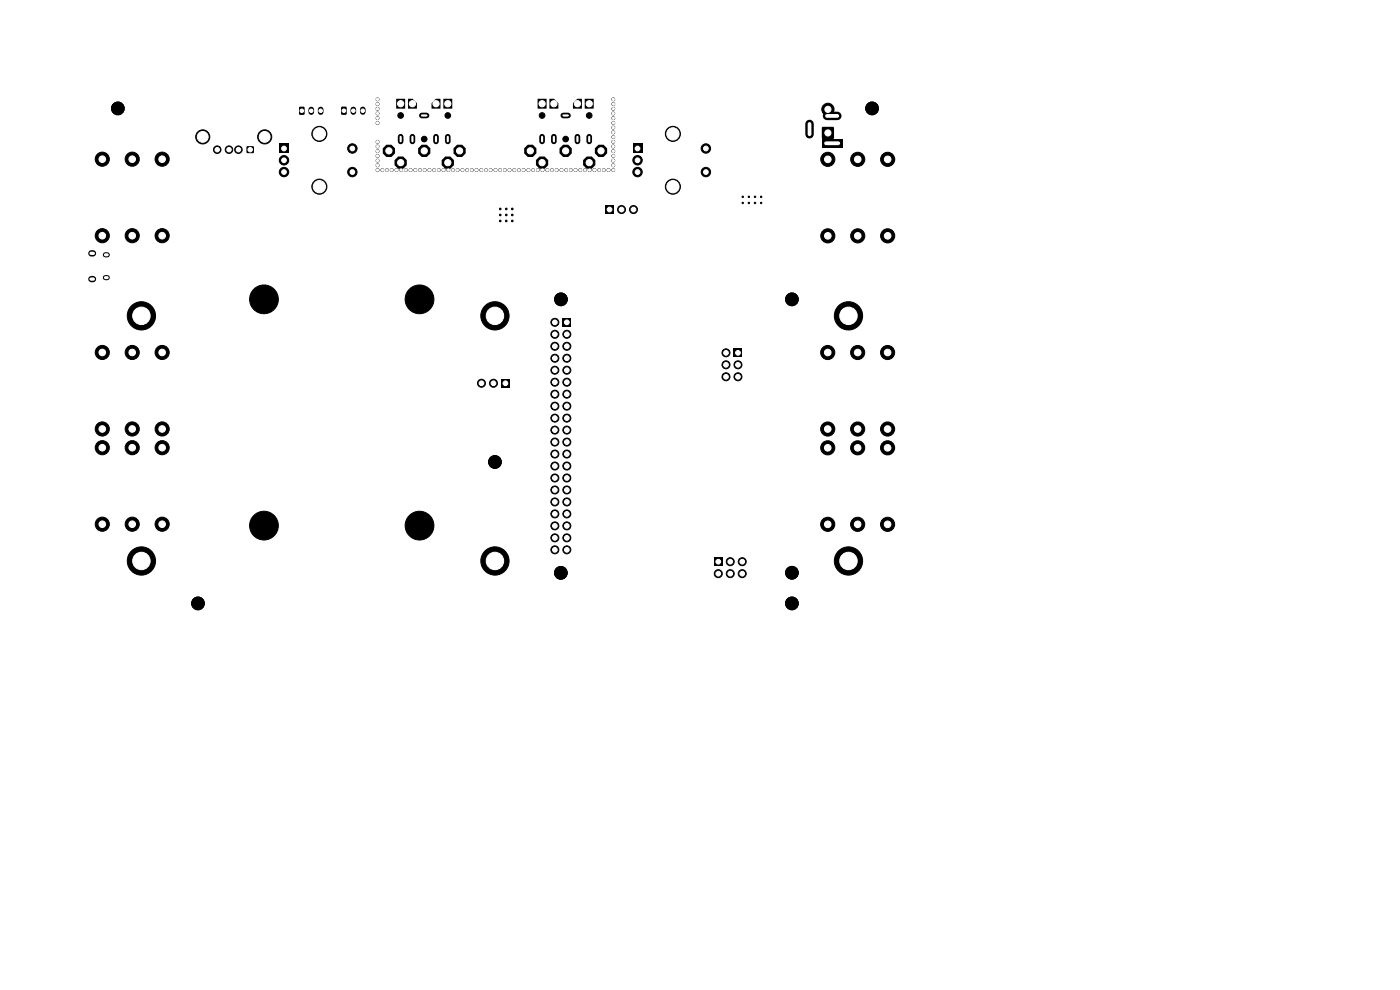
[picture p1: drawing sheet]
<svg xmlns="http://www.w3.org/2000/svg" width="297mm" height="210mm" viewBox="0 0 297 210" stroke-linecap="round" stroke-linejoin="round" font-family="sans-serif">
<g fill="#000" stroke="#000" stroke-width=".21">
<circle cx="21.7" cy="33.8" r="1.5"/>
<circle cx="25" cy="23" r="1.35"/>
<circle cx="28.1" cy="33.8" r="1.5"/>
<circle cx="34.4" cy="33.8" r="1.5"/>
<circle cx="43" cy="29" r="1.5"/>
<circle cx="46.1" cy="31.7" r=".8"/>
<circle cx="48.6" cy="31.7" r=".8"/>
<circle cx="50.6" cy="31.7" r=".8"/>
<circle cx="56.1" cy="29" r="1.5"/>
<circle cx="60.2" cy="36.5" r="1"/>
<circle cx="60.3" cy="34" r="1"/>
<circle cx="67.7" cy="28.4" r="1.6"/>
<circle cx="67.7" cy="39.6" r="1.6"/>
<circle cx="74.7" cy="36.5" r="1"/>
<circle cx="74.7" cy="31.5" r="1"/>
<circle cx="80.1" cy="33.1" r=".3"/>
<circle cx="80.1" cy="24.1" r=".3"/>
<circle cx="80.1" cy="36.1" r=".3"/>
<circle cx="80.1" cy="23.1" r=".3"/>
<circle cx="80.1" cy="21.1" r=".3"/>
<circle cx="80.1" cy="26.1" r=".3"/>
<circle cx="80.1" cy="34.1" r=".3"/>
<circle cx="80.1" cy="31.1" r=".3"/>
<circle cx="80.1" cy="22.1" r=".3"/>
<circle cx="80.1" cy="30.1" r=".3"/>
<circle cx="80.1" cy="25.1" r=".3"/>
<circle cx="80.1" cy="32.1" r=".3"/>
<circle cx="80.1" cy="35.1" r=".3"/>
<circle cx="81.1" cy="36.1" r=".3"/>
<circle cx="82.1" cy="36.1" r=".3"/>
<circle cx="83.1" cy="36.1" r=".3"/>
<circle cx="84.1" cy="36.1" r=".3"/>
<circle cx="85" cy="24.5" r=".6"/>
<circle cx="85.1" cy="36.1" r=".3"/>
<circle cx="86.1" cy="36.1" r=".3"/>
<circle cx="87.1" cy="36.1" r=".3"/>
<circle cx="88.1" cy="36.1" r=".3"/>
<circle cx="89.1" cy="36.1" r=".3"/>
<circle cx="90" cy="29.5" r=".6"/>
<circle cx="90.1" cy="36.1" r=".3"/>
<circle cx="91.1" cy="36.1" r=".3"/>
<circle cx="92.1" cy="36.1" r=".3"/>
<circle cx="93.1" cy="36.1" r=".3"/>
<circle cx="94.1" cy="36.1" r=".3"/>
<circle cx="95" cy="24.5" r=".6"/>
<circle cx="95.1" cy="36.1" r=".3"/>
<circle cx="96.1" cy="36.1" r=".3"/>
<circle cx="97.1" cy="36.1" r=".3"/>
<circle cx="98.1" cy="36.1" r=".3"/>
<circle cx="99.1" cy="36.1" r=".3"/>
<circle cx="100.1" cy="36.1" r=".3"/>
<circle cx="101.1" cy="36.1" r=".3"/>
<circle cx="102.1" cy="36.1" r=".3"/>
<circle cx="103.1" cy="36.1" r=".3"/>
<circle cx="104.1" cy="36.1" r=".3"/>
<circle cx="105.1" cy="36.1" r=".3"/>
<circle cx="106.1" cy="36.1" r=".3"/>
<circle cx="107.1" cy="36.1" r=".3"/>
<circle cx="108.1" cy="36.1" r=".3"/>
<circle cx="109.1" cy="36.1" r=".3"/>
<circle cx="110.1" cy="36.1" r=".3"/>
<circle cx="111.1" cy="36.1" r=".3"/>
<circle cx="112.1" cy="36.1" r=".3"/>
<circle cx="113.1" cy="36.1" r=".3"/>
<circle cx="114.1" cy="36.1" r=".3"/>
<circle cx="115" cy="24.5" r=".6"/>
<circle cx="115.1" cy="36.1" r=".3"/>
<circle cx="116.1" cy="36.1" r=".3"/>
<circle cx="117.1" cy="36.1" r=".3"/>
<circle cx="118.1" cy="36.1" r=".3"/>
<circle cx="119.1" cy="36.1" r=".3"/>
<circle cx="120" cy="29.5" r=".6"/>
<circle cx="120.1" cy="36.1" r=".3"/>
<circle cx="121.1" cy="36.1" r=".3"/>
<circle cx="122.1" cy="36.1" r=".3"/>
<circle cx="123.1" cy="36.1" r=".3"/>
<circle cx="124.1" cy="36.1" r=".3"/>
<circle cx="125" cy="24.5" r=".6"/>
<circle cx="125.1" cy="36.1" r=".3"/>
<circle cx="126.1" cy="36.1" r=".3"/>
<circle cx="127.1" cy="36.1" r=".3"/>
<circle cx="128.1" cy="36.1" r=".3"/>
<circle cx="129.1" cy="36.1" r=".3"/>
<circle cx="130.1" cy="33.1" r=".3"/>
<circle cx="130.1" cy="24.1" r=".3"/>
<circle cx="130.1" cy="29.1" r=".3"/>
<circle cx="130.1" cy="34.1" r=".3"/>
<circle cx="130.1" cy="23.1" r=".3"/>
<circle cx="130.1" cy="36.1" r=".3"/>
<circle cx="130.1" cy="21.1" r=".3"/>
<circle cx="130.1" cy="31.1" r=".3"/>
<circle cx="130.1" cy="26.1" r=".3"/>
<circle cx="130.1" cy="28.1" r=".3"/>
<circle cx="130.1" cy="25.1" r=".3"/>
<circle cx="130.1" cy="32.1" r=".3"/>
<circle cx="130.1" cy="30.1" r=".3"/>
<circle cx="130.1" cy="27.1" r=".3"/>
<circle cx="130.1" cy="35.1" r=".3"/>
<circle cx="130.1" cy="22.1" r=".3"/>
<circle cx="135.2" cy="36.5" r="1"/>
<circle cx="135.2" cy="34" r="1"/>
<circle cx="142.7" cy="28.4" r="1.6"/>
<circle cx="142.8" cy="39.6" r="1.6"/>
<circle cx="149.7" cy="36.5" r="1"/>
<circle cx="149.7" cy="31.5" r="1"/>
<circle cx="175.6" cy="33.8" r="1.5"/>
<circle cx="175.6" cy="23.2" r="1.3"/>
<circle cx="182" cy="33.8" r="1.5"/>
<circle cx="185" cy="23" r="1.35"/>
<circle cx="188.3" cy="33.8" r="1.5"/>
<circle cx="21.7" cy="50" r="1.5"/>
<circle cx="28.1" cy="50" r="1.5"/>
<circle cx="34.4" cy="50" r="1.5"/>
<circle cx="106.1" cy="46.9" r=".17"/>
<circle cx="106.1" cy="44.3" r=".17"/>
<circle cx="106.1" cy="45.6" r=".17"/>
<circle cx="107.4" cy="46.9" r=".17"/>
<circle cx="107.4" cy="45.6" r=".17"/>
<circle cx="107.4" cy="44.3" r=".17"/>
<circle cx="108.7" cy="46.9" r=".17"/>
<circle cx="108.7" cy="44.3" r=".17"/>
<circle cx="108.7" cy="45.6" r=".17"/>
<circle cx="131.9" cy="44.4" r=".85"/>
<circle cx="134.4" cy="44.4" r=".85"/>
<circle cx="157.6" cy="41.8" r=".15"/>
<circle cx="157.6" cy="43.1" r=".15"/>
<circle cx="158.9" cy="43.1" r=".15"/>
<circle cx="158.9" cy="41.8" r=".15"/>
<circle cx="160.2" cy="43.1" r=".15"/>
<circle cx="160.2" cy="41.8" r=".15"/>
<circle cx="161.5" cy="43.1" r=".15"/>
<circle cx="161.5" cy="41.8" r=".15"/>
<circle cx="175.6" cy="50" r="1.5"/>
<circle cx="182" cy="50" r="1.5"/>
<circle cx="188.3" cy="50" r="1.5"/>
<circle cx="21.7" cy="74.8" r="1.5"/>
<circle cx="28.1" cy="74.8" r="1.5"/>
<circle cx="30" cy="67" r="3"/>
<circle cx="34.4" cy="74.8" r="1.5"/>
<circle cx="56" cy="63.5" r="3"/>
<circle cx="56" cy="63.5" r="1.35"/>
<circle cx="89" cy="63.5" r="3"/>
<circle cx="89" cy="63.5" r="1.35"/>
<circle cx="105" cy="67" r="3"/>
<circle cx="117.7" cy="78.5" r=".85"/>
<circle cx="117.7" cy="76" r=".85"/>
<circle cx="117.7" cy="68.4" r=".85"/>
<circle cx="117.7" cy="73.5" r=".85"/>
<circle cx="117.7" cy="70.9" r=".85"/>
<circle cx="119" cy="63.5" r="1.35"/>
<circle cx="120.3" cy="78.5" r=".85"/>
<circle cx="120.3" cy="70.9" r=".85"/>
<circle cx="120.3" cy="73.5" r=".85"/>
<circle cx="120.3" cy="76" r=".85"/>
<circle cx="154" cy="79.9" r=".85"/>
<circle cx="154" cy="74.8" r=".85"/>
<circle cx="154" cy="77.4" r=".85"/>
<circle cx="156.6" cy="79.9" r=".85"/>
<circle cx="156.6" cy="77.4" r=".85"/>
<circle cx="168" cy="63.5" r="1.35"/>
<circle cx="175.6" cy="74.8" r="1.5"/>
<circle cx="180" cy="67" r="3"/>
<circle cx="181.9" cy="74.8" r="1.5"/>
<circle cx="188.3" cy="74.8" r="1.5"/>
<circle cx="21.7" cy="95" r="1.5"/>
<circle cx="21.7" cy="91" r="1.5"/>
<circle cx="28.1" cy="95" r="1.5"/>
<circle cx="28.1" cy="91" r="1.5"/>
<circle cx="34.4" cy="95" r="1.5"/>
<circle cx="34.4" cy="91" r="1.5"/>
<circle cx="102.1" cy="81.3" r=".85"/>
<circle cx="104.7" cy="81.3" r=".85"/>
<circle cx="105" cy="98" r="1.35"/>
<circle cx="117.7" cy="93.8" r=".85"/>
<circle cx="117.7" cy="96.3" r=".85"/>
<circle cx="117.7" cy="88.7" r=".85"/>
<circle cx="117.7" cy="81.1" r=".85"/>
<circle cx="117.7" cy="83.6" r=".85"/>
<circle cx="117.7" cy="86.2" r=".85"/>
<circle cx="117.7" cy="91.2" r=".85"/>
<circle cx="117.7" cy="98.9" r=".85"/>
<circle cx="120.3" cy="86.2" r=".85"/>
<circle cx="120.3" cy="83.6" r=".85"/>
<circle cx="120.3" cy="93.8" r=".85"/>
<circle cx="120.3" cy="96.3" r=".85"/>
<circle cx="120.3" cy="88.7" r=".85"/>
<circle cx="120.3" cy="81.1" r=".85"/>
<circle cx="120.3" cy="91.2" r=".85"/>
<circle cx="120.3" cy="98.9" r=".85"/>
<circle cx="175.6" cy="91" r="1.5"/>
<circle cx="175.6" cy="95" r="1.5"/>
<circle cx="181.9" cy="91" r="1.5"/>
<circle cx="181.9" cy="95" r="1.5"/>
<circle cx="188.3" cy="91" r="1.5"/>
<circle cx="188.3" cy="95" r="1.5"/>
<circle cx="21.7" cy="111.2" r="1.5"/>
<circle cx="28.1" cy="111.2" r="1.5"/>
<circle cx="30" cy="119" r="3"/>
<circle cx="34.4" cy="111.2" r="1.5"/>
<circle cx="56" cy="111.5" r="3"/>
<circle cx="56" cy="111.5" r="1.35"/>
<circle cx="89" cy="111.5" r="3"/>
<circle cx="89" cy="111.5" r="1.35"/>
<circle cx="105" cy="119" r="3"/>
<circle cx="117.7" cy="103.9" r=".85"/>
<circle cx="117.7" cy="106.5" r=".85"/>
<circle cx="117.7" cy="116.6" r=".85"/>
<circle cx="117.7" cy="114.1" r=".85"/>
<circle cx="117.7" cy="109" r=".85"/>
<circle cx="117.7" cy="111.6" r=".85"/>
<circle cx="117.7" cy="101.4" r=".85"/>
<circle cx="120.3" cy="101.4" r=".85"/>
<circle cx="120.3" cy="103.9" r=".85"/>
<circle cx="120.3" cy="114.1" r=".85"/>
<circle cx="120.3" cy="116.6" r=".85"/>
<circle cx="120.3" cy="106.5" r=".85"/>
<circle cx="120.3" cy="109" r=".85"/>
<circle cx="120.3" cy="111.6" r=".85"/>
<circle cx="154.9" cy="119.2" r=".85"/>
<circle cx="157.5" cy="119.2" r=".85"/>
<circle cx="175.6" cy="111.2" r="1.5"/>
<circle cx="180" cy="119" r="3"/>
<circle cx="181.9" cy="111.2" r="1.5"/>
<circle cx="188.3" cy="111.2" r="1.5"/>
<circle cx="42" cy="128" r="1.35"/>
<circle cx="119" cy="121.5" r="1.35"/>
<circle cx="152.4" cy="121.7" r=".85"/>
<circle cx="154.9" cy="121.7" r=".85"/>
<circle cx="157.5" cy="121.7" r=".85"/>
<circle cx="168" cy="121.5" r="1.35"/>
<circle cx="168" cy="128" r="1.35"/>
</g>
<g fill="none" stroke="#000" stroke-width="1.2">
<path d="M66 23.2v.6M68 23.2v.6M75 23.2v.6M77 23.2v.6M85 29v1M87.5 29v1M89.5 24.5h1M92.5 29v1M95 29v1M115 29v1M117.5 29v1M119.5 24.5h1"/>
<path d="M122.5 29v1M125 29v1"/>
</g>
<g fill="#000">
<path d="M52.4 31.1h1.4v1.3h-1.4zM59.2 30.5h2.1v2h-2.1zM63.5 22.7l.9-.1 .2 .2v1.3l-.1 .3h-.8l-.3-.2zM72.4 22.7l.9-.1 .2 .2 .1 1.3-.2 .2-.8 .1-.2-.2zM84.1 21h1.8v2h-1.8zM86.6 21h.9l.9 .9v1.1h-1.8zM91.6 21.9l.9-.9h.9v2h-1.8zM94.1 21h1.8v2h-1.8zM114.1 21h1.8v2h-1.8zM116.6 21h.9l.9 .9v1.1h-1.8zM121.6 21.9l.9-.9h.9v2h-1.8zM124.1 21h1.8v2h-1.8z"/>
<path d="M134.3 30.5h1.9v2h-1.9zM174.4 27h2.5v2.4h-2.5zM174.3 29.5h4.4v1.8h-4.4zM128.5 43.6h1.7v1.7h-1.7zM119.4 67.5h1.7v1.7h-1.7zM155.7 74h1.7v1.7h-1.7zM106.4 80.5h1.7v1.7h-1.7zM151.5 118.3h1.7v1.7h-1.7z"/>
<circle cx="82.5" cy="32" r="1.4"/>
<circle cx="85" cy="34.5" r="1.4"/>
<circle cx="90" cy="32" r="1.4"/>
<circle cx="95" cy="34.5" r="1.4"/>
<circle cx="97.5" cy="32" r="1.4"/>
<circle cx="112.5" cy="32" r="1.4"/>
<circle cx="115" cy="34.5" r="1.4"/>
<circle cx="120" cy="32" r="1.4"/>
<circle cx="125" cy="34.5" r="1.4"/>
<circle cx="127.5" cy="32" r="1.4"/>
</g>
<path d="M171.7 26.3v2.2M175.4 24.6h2.2" fill="none" stroke="#000" stroke-width="1.8"/>
<path d="M19.4 53.7h.3M19.4 59.2h.3" fill="none" stroke="#000" stroke-width="1.3"/>
<path d="M22.4 54.1h.4M22.4 58.9h.4" fill="none" stroke="#000" stroke-width="1.1"/>
<path d="M85 29v1M87.5 29v1M89.5 24.5h1M92.5 29v1M95 29v1M115 29v1M117.5 29v1M119.5 24.5h1M122.5 29v1M125 29v1" fill="none" stroke="#fff" stroke-width=".45"/>
<g fill="#fff" stroke="#fff" stroke-width=".21">
<circle cx="28" cy="50" r=".7"/>
<circle cx="28" cy="33.8" r=".7"/>
<circle cx="21.7" cy="50" r=".7"/>
<circle cx="21.7" cy="33.8" r=".7"/>
<circle cx="34.4" cy="50" r=".7"/>
<circle cx="34.4" cy="33.8" r=".7"/>
<circle cx="28" cy="111.2" r=".7"/>
<circle cx="28" cy="95" r=".7"/>
<circle cx="21.7" cy="111.2" r=".7"/>
<circle cx="21.7" cy="95" r=".7"/>
<circle cx="34.4" cy="111.2" r=".7"/>
<circle cx="34.4" cy="95" r=".7"/>
<circle cx="175.6" cy="28.2" r=".65"/>
<circle cx="175.6" cy="23.2" r=".65"/>
<circle cx="28" cy="91" r=".7"/>
<circle cx="28" cy="74.8" r=".7"/>
<circle cx="21.7" cy="91" r=".7"/>
<circle cx="21.7" cy="74.8" r=".7"/>
<circle cx="34.4" cy="91" r=".7"/>
<circle cx="34.4" cy="74.8" r=".7"/>
<circle cx="181.9" cy="95" r=".7"/>
<circle cx="181.9" cy="111.2" r=".7"/>
<circle cx="188.3" cy="95" r=".7"/>
<circle cx="188.3" cy="111.2" r=".7"/>
<circle cx="175.6" cy="95" r=".7"/>
<circle cx="175.6" cy="111.2" r=".7"/>
<circle cx="129.3" cy="44.5" r=".5"/>
<circle cx="131.9" cy="44.5" r=".5"/>
<circle cx="134.4" cy="44.5" r=".5"/>
<circle cx="80.1" cy="21.1" r=".25"/>
<circle cx="80.1" cy="22.1" r=".25"/>
<circle cx="80.1" cy="23.1" r=".25"/>
<circle cx="80.1" cy="24.1" r=".25"/>
<circle cx="80.1" cy="25.1" r=".25"/>
<circle cx="80.1" cy="26.1" r=".25"/>
<circle cx="80.1" cy="30.1" r=".25"/>
<circle cx="80.1" cy="31.1" r=".25"/>
<circle cx="80.1" cy="32.1" r=".25"/>
<circle cx="80.1" cy="33.1" r=".25"/>
<circle cx="80.1" cy="34.1" r=".25"/>
<circle cx="80.1" cy="35.1" r=".25"/>
<circle cx="80.1" cy="36.1" r=".25"/>
<circle cx="81.1" cy="36.1" r=".25"/>
<circle cx="82.1" cy="36.1" r=".25"/>
<circle cx="83.1" cy="36.1" r=".25"/>
<circle cx="84.1" cy="36.1" r=".25"/>
<circle cx="85.1" cy="36.1" r=".25"/>
<circle cx="86.1" cy="36.1" r=".25"/>
<circle cx="87.1" cy="36.1" r=".25"/>
<circle cx="88.1" cy="36.1" r=".25"/>
<circle cx="89.1" cy="36.1" r=".25"/>
<circle cx="90.1" cy="36.1" r=".25"/>
<circle cx="91.1" cy="36.1" r=".25"/>
<circle cx="92.1" cy="36.1" r=".25"/>
<circle cx="93.1" cy="36.1" r=".25"/>
<circle cx="94.1" cy="36.1" r=".25"/>
<circle cx="95.1" cy="36.1" r=".25"/>
<circle cx="96.1" cy="36.1" r=".25"/>
<circle cx="97.1" cy="36.1" r=".25"/>
<circle cx="98.1" cy="36.1" r=".25"/>
<circle cx="99.1" cy="36.1" r=".25"/>
<circle cx="100.1" cy="36.1" r=".25"/>
<circle cx="101.1" cy="36.1" r=".25"/>
<circle cx="102.1" cy="36.1" r=".25"/>
<circle cx="103.1" cy="36.1" r=".25"/>
<circle cx="104.1" cy="36.1" r=".25"/>
<circle cx="105.1" cy="36.1" r=".25"/>
<circle cx="106.1" cy="36.1" r=".25"/>
<circle cx="107.1" cy="36.1" r=".25"/>
<circle cx="108.1" cy="36.1" r=".25"/>
<circle cx="109.1" cy="36.1" r=".25"/>
<circle cx="110.1" cy="36.1" r=".25"/>
<circle cx="111.1" cy="36.1" r=".25"/>
<circle cx="112.1" cy="36.1" r=".25"/>
<circle cx="113.1" cy="36.1" r=".25"/>
<circle cx="114.1" cy="36.1" r=".25"/>
<circle cx="115.1" cy="36.1" r=".25"/>
<circle cx="116.1" cy="36.1" r=".25"/>
<circle cx="117.1" cy="36.1" r=".25"/>
<circle cx="118.1" cy="36.1" r=".25"/>
<circle cx="119.1" cy="36.1" r=".25"/>
<circle cx="120.1" cy="36.1" r=".25"/>
<circle cx="121.1" cy="36.1" r=".25"/>
<circle cx="122.1" cy="36.1" r=".25"/>
<circle cx="123.1" cy="36.1" r=".25"/>
<circle cx="124.1" cy="36.1" r=".25"/>
<circle cx="125.1" cy="36.1" r=".25"/>
<circle cx="126.1" cy="36.1" r=".25"/>
<circle cx="127.1" cy="36.1" r=".25"/>
<circle cx="128.1" cy="36.1" r=".25"/>
<circle cx="129.1" cy="36.1" r=".25"/>
<circle cx="130.1" cy="21.1" r=".25"/>
<circle cx="130.1" cy="22.1" r=".25"/>
<circle cx="130.1" cy="23.1" r=".25"/>
<circle cx="130.1" cy="24.1" r=".25"/>
<circle cx="130.1" cy="25.1" r=".25"/>
<circle cx="130.1" cy="26.1" r=".25"/>
<circle cx="130.1" cy="27.1" r=".25"/>
<circle cx="130.1" cy="28.1" r=".25"/>
<circle cx="130.1" cy="29.1" r=".25"/>
<circle cx="130.1" cy="30.1" r=".25"/>
<circle cx="130.1" cy="31.1" r=".25"/>
<circle cx="130.1" cy="32.1" r=".25"/>
<circle cx="130.1" cy="33.1" r=".25"/>
<circle cx="130.1" cy="34.1" r=".25"/>
<circle cx="130.1" cy="35.1" r=".25"/>
<circle cx="130.1" cy="36.1" r=".25"/>
<circle cx="182" cy="33.8" r=".7"/>
<circle cx="182" cy="50" r=".7"/>
<circle cx="188.3" cy="33.8" r=".7"/>
<circle cx="188.3" cy="50" r=".7"/>
<circle cx="175.6" cy="33.8" r=".7"/>
<circle cx="175.6" cy="50" r=".7"/>
<circle cx="112.5" cy="32" r=".66"/>
<circle cx="120" cy="32" r=".66"/>
<circle cx="127.5" cy="32" r=".66"/>
<circle cx="115" cy="34.5" r=".66"/>
<circle cx="125" cy="34.5" r=".66"/>
<circle cx="122.5" cy="22" r=".66"/>
<circle cx="125" cy="22" r=".66"/>
<circle cx="115" cy="22" r=".66"/>
<circle cx="117.5" cy="22" r=".66"/>
<circle cx="60.2" cy="31.5" r=".5"/>
<circle cx="60.2" cy="36.5" r=".5"/>
<circle cx="60.2" cy="34" r=".5"/>
<circle cx="67.7" cy="28.4" r="1.3"/>
<circle cx="67.7" cy="39.6" r="1.3"/>
<circle cx="74.8" cy="36.5" r=".5"/>
<circle cx="74.8" cy="31.5" r=".5"/>
<circle cx="107.2" cy="81.3" r=".5"/>
<circle cx="104.7" cy="81.3" r=".5"/>
<circle cx="102.1" cy="81.3" r=".5"/>
<circle cx="181.9" cy="74.8" r=".7"/>
<circle cx="181.9" cy="91" r=".7"/>
<circle cx="188.3" cy="74.8" r=".7"/>
<circle cx="188.3" cy="91" r=".7"/>
<circle cx="175.6" cy="74.8" r=".7"/>
<circle cx="175.6" cy="91" r=".7"/>
<circle cx="53.1" cy="31.8" r=".47"/>
<circle cx="50.6" cy="31.8" r=".47"/>
<circle cx="48.6" cy="31.8" r=".47"/>
<circle cx="46.1" cy="31.8" r=".47"/>
<circle cx="56.1" cy="29" r="1.15"/>
<circle cx="43" cy="29" r="1.15"/>
<circle cx="135.3" cy="31.5" r=".5"/>
<circle cx="135.3" cy="36.5" r=".5"/>
<circle cx="135.3" cy="34" r=".5"/>
<circle cx="142.8" cy="28.4" r="1.3"/>
<circle cx="142.8" cy="39.6" r="1.3"/>
<circle cx="149.7" cy="36.5" r=".5"/>
<circle cx="149.7" cy="31.5" r=".5"/>
<circle cx="82.5" cy="32" r=".66"/>
<circle cx="90" cy="32" r=".66"/>
<circle cx="97.5" cy="32" r=".66"/>
<circle cx="85" cy="34.5" r=".66"/>
<circle cx="95" cy="34.5" r=".66"/>
<circle cx="92.5" cy="22" r=".66"/>
<circle cx="95" cy="22" r=".66"/>
<circle cx="85" cy="22" r=".66"/>
<circle cx="87.5" cy="22" r=".66"/>
<circle cx="30" cy="119" r="1.85"/>
<circle cx="105" cy="67" r="1.85"/>
<circle cx="30" cy="67" r="1.85"/>
<circle cx="180" cy="67" r="1.85"/>
<circle cx="105" cy="119" r="1.85"/>
<circle cx="73" cy="23.5" r=".37"/>
<circle cx="75" cy="23.5" r=".37"/>
<circle cx="77" cy="23.5" r=".37"/>
<circle cx="180" cy="119" r="1.85"/>
<circle cx="120.3" cy="68.4" r=".5"/>
<circle cx="117.7" cy="68.4" r=".5"/>
<circle cx="120.3" cy="70.9" r=".5"/>
<circle cx="117.7" cy="70.9" r=".5"/>
<circle cx="120.3" cy="73.5" r=".5"/>
<circle cx="117.7" cy="73.5" r=".5"/>
<circle cx="120.3" cy="76" r=".5"/>
<circle cx="117.7" cy="76" r=".5"/>
<circle cx="120.3" cy="78.5" r=".5"/>
<circle cx="117.7" cy="78.5" r=".5"/>
<circle cx="120.3" cy="81.1" r=".5"/>
<circle cx="117.7" cy="81.1" r=".5"/>
<circle cx="120.3" cy="83.6" r=".5"/>
<circle cx="117.7" cy="83.6" r=".5"/>
<circle cx="120.3" cy="86.2" r=".5"/>
<circle cx="117.7" cy="86.2" r=".5"/>
<circle cx="120.3" cy="88.7" r=".5"/>
<circle cx="117.7" cy="88.7" r=".5"/>
<circle cx="120.3" cy="91.2" r=".5"/>
<circle cx="117.7" cy="91.2" r=".5"/>
<circle cx="120.3" cy="93.8" r=".5"/>
<circle cx="117.7" cy="93.8" r=".5"/>
<circle cx="120.3" cy="96.3" r=".5"/>
<circle cx="117.7" cy="96.3" r=".5"/>
<circle cx="120.3" cy="98.9" r=".5"/>
<circle cx="117.7" cy="98.9" r=".5"/>
<circle cx="120.3" cy="101.4" r=".5"/>
<circle cx="117.7" cy="101.4" r=".5"/>
<circle cx="120.3" cy="103.9" r=".5"/>
<circle cx="117.7" cy="103.9" r=".5"/>
<circle cx="120.3" cy="106.5" r=".5"/>
<circle cx="117.7" cy="106.5" r=".5"/>
<circle cx="120.3" cy="109" r=".5"/>
<circle cx="117.7" cy="109" r=".5"/>
<circle cx="120.3" cy="111.6" r=".5"/>
<circle cx="117.7" cy="111.6" r=".5"/>
<circle cx="120.3" cy="114.1" r=".5"/>
<circle cx="117.7" cy="114.1" r=".5"/>
<circle cx="120.3" cy="116.6" r=".5"/>
<circle cx="117.7" cy="116.6" r=".5"/>
<circle cx="156.6" cy="74.8" r=".5"/>
<circle cx="154" cy="74.8" r=".5"/>
<circle cx="156.6" cy="77.4" r=".5"/>
<circle cx="154" cy="77.4" r=".5"/>
<circle cx="156.6" cy="79.9" r=".5"/>
<circle cx="154" cy="79.9" r=".5"/>
<circle cx="152.4" cy="119.2" r=".5"/>
<circle cx="152.4" cy="121.7" r=".5"/>
<circle cx="154.9" cy="119.2" r=".5"/>
<circle cx="154.9" cy="121.7" r=".5"/>
<circle cx="157.5" cy="119.2" r=".5"/>
<circle cx="157.5" cy="121.7" r=".5"/>
<circle cx="64" cy="23.5" r=".38"/>
<circle cx="66" cy="23.5" r=".38"/>
<circle cx="68" cy="23.5" r=".38"/>
</g>
<path d="M171.7 26.3v2.2M175.2 30.4h2.6M175.4 24.6h2.2" fill="none" stroke="#fff" stroke-width=".8"/>
<path d="M19.3 53.7h.5M19.3 59.2h.5" fill="none" stroke="#fff" stroke-width=".7"/>
<path d="M22.4 54.1h.4M22.4 58.9h.4" fill="none" stroke="#fff" stroke-width=".65"/>
</svg>
